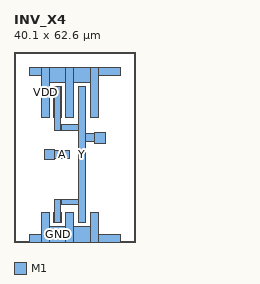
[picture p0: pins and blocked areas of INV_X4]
MACRO INV_X4
  CLASS CORE ;
  ORIGIN 0 0 ;
  SIZE 40.100 BY 62.600 ;
  SYMMETRY X Y ;
  SITE TR1um_site ;
  PIN Y
    DIRECTION OUTPUT ;
    USE SIGNAL ;
    PORT
      LAYER M1 ;
        RECT 13.100 6.400 13.500 9.800 ;
      LAYER M1 ;
        RECT 13.100 41.000 13.500 51.200 ;
      LAYER M1 ;
        RECT 13.500 6.400 15.300 14.000 ;
      LAYER M1 ;
        RECT 13.500 36.800 15.300 51.200 ;
      LAYER M1 ;
        RECT 15.300 6.400 15.700 9.800 ;
      LAYER M1 ;
        RECT 15.300 12.200 15.700 14.000 ;
      LAYER M1 ;
        RECT 15.300 36.800 15.700 38.600 ;
      LAYER M1 ;
        RECT 15.300 41.000 15.700 51.200 ;
      LAYER M1 ;
        RECT 15.700 12.200 21.100 14.000 ;
      LAYER M1 ;
        RECT 15.700 36.800 21.100 38.600 ;
      LAYER M1 ;
        RECT 21.100 6.400 23.700 51.200 ;
      LAYER M1 ;
        RECT 23.700 33.000 26.600 35.600 ;
      LAYER M1 ;
        RECT 26.600 32.600 30.000 36.000 ;
    END
  END Y
  PIN A
    DIRECTION INPUT ;
    USE SIGNAL ;
    PORT
      LAYER M1 ;
        RECT 10.100 27.100 13.500 30.500 ;
      LAYER M1 ;
        RECT 13.500 27.500 18.400 30.100 ;
    END
  END A
  PIN VDD
    DIRECTION INOUT ;
    USE POWER ;
    PORT
      LAYER M1 ;
        RECT 5.000 55.000 9.100 57.600 ;
      LAYER M1 ;
        RECT 9.100 41.000 11.700 57.600 ;
      LAYER M1 ;
        RECT 11.700 52.600 17.100 57.600 ;
      LAYER M1 ;
        RECT 17.100 41.000 19.700 57.600 ;
      LAYER M1 ;
        RECT 19.700 52.600 25.100 57.600 ;
      LAYER M1 ;
        RECT 25.100 41.000 27.700 57.600 ;
      LAYER M1 ;
        RECT 27.700 55.000 35.100 57.600 ;
    END
  END VDD
  PIN GND
    DIRECTION INOUT ;
    USE GROUND ;
    PORT
      LAYER M1 ;
        RECT 5.000 0.000 9.100 2.600 ;
      LAYER M1 ;
        RECT 9.100 0.000 11.700 9.800 ;
      LAYER M1 ;
        RECT 11.700 0.000 17.100 5.000 ;
      LAYER M1 ;
        RECT 17.100 0.000 19.700 9.800 ;
      LAYER M1 ;
        RECT 19.700 0.000 25.100 5.000 ;
      LAYER M1 ;
        RECT 25.100 0.000 27.700 9.800 ;
      LAYER M1 ;
        RECT 27.700 0.000 35.100 2.600 ;
    END
  END GND
END INV_X4
